VERSION 5.7 ;
  NOWIREEXTENSIONATPIN ON ;
  DIVIDERCHAR "/" ;
  BUSBITCHARS "[]" ;
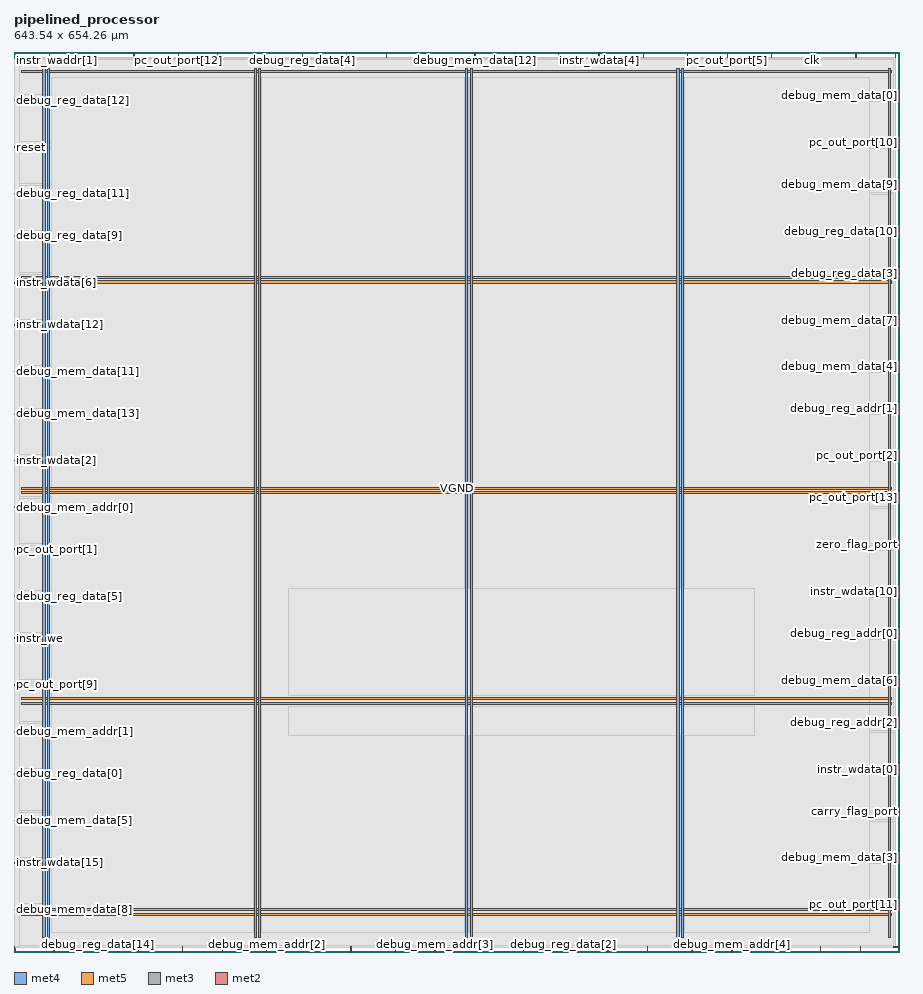
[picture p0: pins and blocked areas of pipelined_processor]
MACRO pipelined_processor
  CLASS BLOCK ;
  FOREIGN pipelined_processor ;
  ORIGIN 0.000 0.000 ;
  SIZE 643.540 BY 654.260 ;
  PIN VGND
    DIRECTION INOUT ;
    USE GROUND ;
    PORT
      LAYER met4 ;
        RECT 24.340 10.640 25.940 642.160 ;
    END
    PORT
      LAYER met4 ;
        RECT 177.940 10.640 179.540 642.160 ;
    END
    PORT
      LAYER met4 ;
        RECT 331.540 10.640 333.140 642.160 ;
    END
    PORT
      LAYER met4 ;
        RECT 485.140 10.640 486.740 642.160 ;
    END
    PORT
      LAYER met5 ;
        RECT 5.280 30.030 638.260 31.630 ;
    END
    PORT
      LAYER met5 ;
        RECT 5.280 183.210 638.260 184.810 ;
    END
    PORT
      LAYER met5 ;
        RECT 5.280 336.390 638.260 337.990 ;
    END
    PORT
      LAYER met5 ;
        RECT 5.280 489.570 638.260 491.170 ;
    END
  END VGND
  PIN VPWR
    DIRECTION INOUT ;
    USE POWER ;
    PORT
      LAYER met4 ;
        RECT 21.040 10.640 22.640 642.160 ;
    END
    PORT
      LAYER met4 ;
        RECT 174.640 10.640 176.240 642.160 ;
    END
    PORT
      LAYER met4 ;
        RECT 328.240 10.640 329.840 642.160 ;
    END
    PORT
      LAYER met4 ;
        RECT 481.840 10.640 483.440 642.160 ;
    END
    PORT
      LAYER met4 ;
        RECT 635.440 10.640 637.040 642.160 ;
    END
    PORT
      LAYER met5 ;
        RECT 5.280 26.730 638.260 28.330 ;
    END
    PORT
      LAYER met5 ;
        RECT 5.280 179.910 638.260 181.510 ;
    END
    PORT
      LAYER met5 ;
        RECT 5.280 333.090 638.260 334.690 ;
    END
    PORT
      LAYER met5 ;
        RECT 5.280 486.270 638.260 487.870 ;
    END
    PORT
      LAYER met5 ;
        RECT 5.280 639.450 638.260 641.050 ;
    END
  END VPWR
  PIN carry_flag_port
    DIRECTION OUTPUT TRISTATE ;
    USE SIGNAL ;
    ANTENNADIFFAREA 0.795200 ;
    PORT
      LAYER met3 ;
        RECT 639.540 102.040 643.540 102.640 ;
    END
  END carry_flag_port
  PIN clk
    DIRECTION INPUT ;
    USE SIGNAL ;
    ANTENNAGATEAREA 1.286700 ;
    ANTENNADIFFAREA 0.434700 ;
    PORT
      LAYER met2 ;
        RECT 579.690 650.260 579.970 654.260 ;
    END
  END clk
  PIN debug_mem_addr[0]
    DIRECTION INPUT ;
    USE SIGNAL ;
    ANTENNAGATEAREA 0.247500 ;
    PORT
      LAYER met3 ;
        RECT 0.000 323.040 4.000 323.640 ;
    END
  END debug_mem_addr[0]
  PIN debug_mem_addr[1]
    DIRECTION INPUT ;
    USE SIGNAL ;
    ANTENNAGATEAREA 0.213000 ;
    PORT
      LAYER met3 ;
        RECT 0.000 159.840 4.000 160.440 ;
    END
  END debug_mem_addr[1]
  PIN debug_mem_addr[2]
    DIRECTION INPUT ;
    USE SIGNAL ;
    ANTENNAGATEAREA 0.213000 ;
    PORT
      LAYER met2 ;
        RECT 183.630 0.000 183.910 4.000 ;
    END
  END debug_mem_addr[2]
  PIN debug_mem_addr[3]
    DIRECTION INPUT ;
    USE SIGNAL ;
    ANTENNAGATEAREA 0.159000 ;
    PORT
      LAYER met2 ;
        RECT 305.990 0.000 306.270 4.000 ;
    END
  END debug_mem_addr[3]
  PIN debug_mem_addr[4]
    DIRECTION INPUT ;
    USE SIGNAL ;
    ANTENNAGATEAREA 0.126000 ;
    PORT
      LAYER met2 ;
        RECT 521.730 0.000 522.010 4.000 ;
    END
  END debug_mem_addr[4]
  PIN debug_mem_addr[5]
    DIRECTION INPUT ;
    USE SIGNAL ;
    ANTENNAGATEAREA 0.126000 ;
    PORT
      LAYER met2 ;
        RECT 553.930 0.000 554.210 4.000 ;
    END
  END debug_mem_addr[5]
  PIN debug_mem_data[0]
    DIRECTION OUTPUT TRISTATE ;
    USE SIGNAL ;
    ANTENNADIFFAREA 0.445500 ;
    PORT
      LAYER met3 ;
        RECT 639.540 622.240 643.540 622.840 ;
    END
  END debug_mem_data[0]
  PIN debug_mem_data[10]
    DIRECTION OUTPUT TRISTATE ;
    USE SIGNAL ;
    ANTENNADIFFAREA 0.795200 ;
    PORT
      LAYER met2 ;
        RECT 87.030 650.260 87.310 654.260 ;
    END
  END debug_mem_data[10]
  PIN debug_mem_data[11]
    DIRECTION OUTPUT TRISTATE ;
    USE SIGNAL ;
    ANTENNADIFFAREA 0.795200 ;
    PORT
      LAYER met3 ;
        RECT 0.000 421.640 4.000 422.240 ;
    END
  END debug_mem_data[11]
  PIN debug_mem_data[12]
    DIRECTION OUTPUT TRISTATE ;
    USE SIGNAL ;
    ANTENNADIFFAREA 0.795200 ;
    PORT
      LAYER met2 ;
        RECT 334.970 650.260 335.250 654.260 ;
    END
  END debug_mem_data[12]
  PIN debug_mem_data[13]
    DIRECTION OUTPUT TRISTATE ;
    USE SIGNAL ;
    ANTENNADIFFAREA 0.795200 ;
    PORT
      LAYER met3 ;
        RECT 0.000 391.040 4.000 391.640 ;
    END
  END debug_mem_data[13]
  PIN debug_mem_data[14]
    DIRECTION OUTPUT TRISTATE ;
    USE SIGNAL ;
    ANTENNADIFFAREA 0.795200 ;
    PORT
      LAYER met3 ;
        RECT 639.540 3.440 643.540 4.040 ;
    END
  END debug_mem_data[14]
  PIN debug_mem_data[15]
    DIRECTION OUTPUT TRISTATE ;
    USE SIGNAL ;
    ANTENNADIFFAREA 0.795200 ;
    PORT
      LAYER met2 ;
        RECT 615.110 0.000 615.390 4.000 ;
    END
  END debug_mem_data[15]
  PIN debug_mem_data[1]
    DIRECTION OUTPUT TRISTATE ;
    USE SIGNAL ;
    ANTENNADIFFAREA 0.795200 ;
    PORT
      LAYER met2 ;
        RECT 363.950 650.260 364.230 654.260 ;
    END
  END debug_mem_data[1]
  PIN debug_mem_data[2]
    DIRECTION OUTPUT TRISTATE ;
    USE SIGNAL ;
    ANTENNADIFFAREA 0.795200 ;
    PORT
      LAYER met2 ;
        RECT 489.530 650.260 489.810 654.260 ;
    END
  END debug_mem_data[2]
  PIN debug_mem_data[3]
    DIRECTION OUTPUT TRISTATE ;
    USE SIGNAL ;
    ANTENNADIFFAREA 0.795200 ;
    PORT
      LAYER met3 ;
        RECT 639.540 68.040 643.540 68.640 ;
    END
  END debug_mem_data[3]
  PIN debug_mem_data[4]
    DIRECTION OUTPUT TRISTATE ;
    USE SIGNAL ;
    ANTENNADIFFAREA 0.445500 ;
    PORT
      LAYER met3 ;
        RECT 639.540 425.040 643.540 425.640 ;
    END
  END debug_mem_data[4]
  PIN debug_mem_data[5]
    DIRECTION OUTPUT TRISTATE ;
    USE SIGNAL ;
    ANTENNADIFFAREA 0.795200 ;
    PORT
      LAYER met3 ;
        RECT 0.000 95.240 4.000 95.840 ;
    END
  END debug_mem_data[5]
  PIN debug_mem_data[6]
    DIRECTION OUTPUT TRISTATE ;
    USE SIGNAL ;
    ANTENNADIFFAREA 0.445500 ;
    PORT
      LAYER met3 ;
        RECT 639.540 197.240 643.540 197.840 ;
    END
  END debug_mem_data[6]
  PIN debug_mem_data[7]
    DIRECTION OUTPUT TRISTATE ;
    USE SIGNAL ;
    ANTENNADIFFAREA 0.445500 ;
    PORT
      LAYER met3 ;
        RECT 639.540 459.040 643.540 459.640 ;
    END
  END debug_mem_data[7]
  PIN debug_mem_data[8]
    DIRECTION OUTPUT TRISTATE ;
    USE SIGNAL ;
    ANTENNADIFFAREA 0.795200 ;
    PORT
      LAYER met3 ;
        RECT 0.000 30.640 4.000 31.240 ;
    END
  END debug_mem_data[8]
  PIN debug_mem_data[9]
    DIRECTION OUTPUT TRISTATE ;
    USE SIGNAL ;
    ANTENNADIFFAREA 0.795200 ;
    PORT
      LAYER met3 ;
        RECT 639.540 557.640 643.540 558.240 ;
    END
  END debug_mem_data[9]
  PIN debug_reg_addr[0]
    DIRECTION INPUT ;
    USE SIGNAL ;
    ANTENNAGATEAREA 0.247500 ;
    PORT
      LAYER met3 ;
        RECT 639.540 231.240 643.540 231.840 ;
    END
  END debug_reg_addr[0]
  PIN debug_reg_addr[1]
    DIRECTION INPUT ;
    USE SIGNAL ;
    ANTENNAGATEAREA 0.213000 ;
    PORT
      LAYER met3 ;
        RECT 639.540 394.440 643.540 395.040 ;
    END
  END debug_reg_addr[1]
  PIN debug_reg_addr[2]
    DIRECTION INPUT ;
    USE SIGNAL ;
    ANTENNAGATEAREA 0.426000 ;
    PORT
      LAYER met3 ;
        RECT 639.540 166.640 643.540 167.240 ;
    END
  END debug_reg_addr[2]
  PIN debug_reg_data[0]
    DIRECTION OUTPUT TRISTATE ;
    USE SIGNAL ;
    ANTENNADIFFAREA 0.795200 ;
    PORT
      LAYER met3 ;
        RECT 0.000 129.240 4.000 129.840 ;
    END
  END debug_reg_data[0]
  PIN debug_reg_data[10]
    DIRECTION OUTPUT TRISTATE ;
    USE SIGNAL ;
    ANTENNADIFFAREA 0.795200 ;
    PORT
      LAYER met3 ;
        RECT 639.540 523.640 643.540 524.240 ;
    END
  END debug_reg_data[10]
  PIN debug_reg_data[11]
    DIRECTION OUTPUT TRISTATE ;
    USE SIGNAL ;
    ANTENNADIFFAREA 0.795200 ;
    PORT
      LAYER met3 ;
        RECT 0.000 550.840 4.000 551.440 ;
    END
  END debug_reg_data[11]
  PIN debug_reg_data[12]
    DIRECTION OUTPUT TRISTATE ;
    USE SIGNAL ;
    ANTENNADIFFAREA 0.795200 ;
    PORT
      LAYER met3 ;
        RECT 0.000 618.840 4.000 619.440 ;
    END
  END debug_reg_data[12]
  PIN debug_reg_data[13]
    DIRECTION OUTPUT TRISTATE ;
    USE SIGNAL ;
    ANTENNADIFFAREA 0.795200 ;
    PORT
      LAYER met3 ;
        RECT 0.000 649.440 4.000 650.040 ;
    END
  END debug_reg_data[13]
  PIN debug_reg_data[14]
    DIRECTION OUTPUT TRISTATE ;
    USE SIGNAL ;
    ANTENNADIFFAREA 0.795200 ;
    PORT
      LAYER met2 ;
        RECT 61.270 0.000 61.550 4.000 ;
    END
  END debug_reg_data[14]
  PIN debug_reg_data[15]
    DIRECTION OUTPUT TRISTATE ;
    USE SIGNAL ;
    ANTENNADIFFAREA 0.795200 ;
    PORT
      LAYER met2 ;
        RECT 396.150 650.260 396.430 654.260 ;
    END
  END debug_reg_data[15]
  PIN debug_reg_data[1]
    DIRECTION OUTPUT TRISTATE ;
    USE SIGNAL ;
    ANTENNADIFFAREA 0.795200 ;
    PORT
      LAYER met2 ;
        RECT 244.810 0.000 245.090 4.000 ;
    END
  END debug_reg_data[1]
  PIN debug_reg_data[2]
    DIRECTION OUTPUT TRISTATE ;
    USE SIGNAL ;
    ANTENNADIFFAREA 0.795200 ;
    PORT
      LAYER met2 ;
        RECT 399.370 0.000 399.650 4.000 ;
    END
  END debug_reg_data[2]
  PIN debug_reg_data[3]
    DIRECTION OUTPUT TRISTATE ;
    USE SIGNAL ;
    ANTENNADIFFAREA 0.445500 ;
    PORT
      LAYER met3 ;
        RECT 639.540 493.040 643.540 493.640 ;
    END
  END debug_reg_data[3]
  PIN debug_reg_data[4]
    DIRECTION OUTPUT TRISTATE ;
    USE SIGNAL ;
    ANTENNADIFFAREA 0.795200 ;
    PORT
      LAYER met2 ;
        RECT 209.390 650.260 209.670 654.260 ;
    END
  END debug_reg_data[4]
  PIN debug_reg_data[5]
    DIRECTION OUTPUT TRISTATE ;
    USE SIGNAL ;
    ANTENNADIFFAREA 0.795200 ;
    PORT
      LAYER met3 ;
        RECT 0.000 258.440 4.000 259.040 ;
    END
  END debug_reg_data[5]
  PIN debug_reg_data[6]
    DIRECTION OUTPUT TRISTATE ;
    USE SIGNAL ;
    ANTENNADIFFAREA 0.795200 ;
    PORT
      LAYER met2 ;
        RECT 151.430 0.000 151.710 4.000 ;
    END
  END debug_reg_data[6]
  PIN debug_reg_data[7]
    DIRECTION OUTPUT TRISTATE ;
    USE SIGNAL ;
    ANTENNADIFFAREA 0.795200 ;
    PORT
      LAYER met2 ;
        RECT 492.750 0.000 493.030 4.000 ;
    END
  END debug_reg_data[7]
  PIN debug_reg_data[8]
    DIRECTION OUTPUT TRISTATE ;
    USE SIGNAL ;
    ANTENNADIFFAREA 0.795200 ;
    PORT
      LAYER met2 ;
        RECT 457.330 650.260 457.610 654.260 ;
    END
  END debug_reg_data[8]
  PIN debug_reg_data[9]
    DIRECTION OUTPUT TRISTATE ;
    USE SIGNAL ;
    ANTENNADIFFAREA 0.795200 ;
    PORT
      LAYER met3 ;
        RECT 0.000 520.240 4.000 520.840 ;
    END
  END debug_reg_data[9]
  PIN instr_waddr[0]
    DIRECTION INPUT ;
    USE SIGNAL ;
    ANTENNAGATEAREA 0.426000 ;
    PORT
      LAYER met2 ;
        RECT 370.390 0.000 370.670 4.000 ;
    END
  END instr_waddr[0]
  PIN instr_waddr[1]
    DIRECTION INPUT ;
    USE SIGNAL ;
    ANTENNAGATEAREA 0.159000 ;
    PORT
      LAYER met2 ;
        RECT 25.850 650.260 26.130 654.260 ;
    END
  END instr_waddr[1]
  PIN instr_waddr[2]
    DIRECTION INPUT ;
    USE SIGNAL ;
    ANTENNAGATEAREA 0.495000 ;
    PORT
      LAYER met2 ;
        RECT 586.130 0.000 586.410 4.000 ;
    END
  END instr_waddr[2]
  PIN instr_waddr[3]
    DIRECTION INPUT ;
    USE SIGNAL ;
    ANTENNAGATEAREA 0.213000 ;
    PORT
      LAYER met2 ;
        RECT 241.590 650.260 241.870 654.260 ;
    END
  END instr_waddr[3]
  PIN instr_wdata[0]
    DIRECTION INPUT ;
    USE SIGNAL ;
    ANTENNAGATEAREA 0.495000 ;
    PORT
      LAYER met3 ;
        RECT 639.540 132.640 643.540 133.240 ;
    END
  END instr_wdata[0]
  PIN instr_wdata[10]
    DIRECTION INPUT ;
    USE SIGNAL ;
    ANTENNAGATEAREA 0.247500 ;
    PORT
      LAYER met3 ;
        RECT 639.540 261.840 643.540 262.440 ;
    END
  END instr_wdata[10]
  PIN instr_wdata[11]
    DIRECTION INPUT ;
    USE SIGNAL ;
    ANTENNAGATEAREA 0.426000 ;
    PORT
      LAYER met2 ;
        RECT 460.550 0.000 460.830 4.000 ;
    END
  END instr_wdata[11]
  PIN instr_wdata[12]
    DIRECTION INPUT ;
    USE SIGNAL ;
    ANTENNAGATEAREA 0.196500 ;
    PORT
      LAYER met3 ;
        RECT 0.000 455.640 4.000 456.240 ;
    END
  END instr_wdata[12]
  PIN instr_wdata[13]
    DIRECTION INPUT ;
    USE SIGNAL ;
    ANTENNAGATEAREA 0.159000 ;
    PORT
      LAYER met2 ;
        RECT 180.410 650.260 180.690 654.260 ;
    END
  END instr_wdata[13]
  PIN instr_wdata[14]
    DIRECTION INPUT ;
    USE SIGNAL ;
    ANTENNAGATEAREA 0.213000 ;
    PORT
      LAYER met2 ;
        RECT 302.770 650.260 303.050 654.260 ;
    END
  END instr_wdata[14]
  PIN instr_wdata[15]
    DIRECTION INPUT ;
    USE SIGNAL ;
    ANTENNAGATEAREA 0.213000 ;
    PORT
      LAYER met3 ;
        RECT 0.000 64.640 4.000 65.240 ;
    END
  END instr_wdata[15]
  PIN instr_wdata[1]
    DIRECTION INPUT ;
    USE SIGNAL ;
    ANTENNAGATEAREA 0.213000 ;
    PORT
      LAYER met2 ;
        RECT 0.090 0.000 0.370 4.000 ;
    END
  END instr_wdata[1]
  PIN instr_wdata[2]
    DIRECTION INPUT ;
    USE SIGNAL ;
    ANTENNAGATEAREA 0.126000 ;
    PORT
      LAYER met3 ;
        RECT 0.000 357.040 4.000 357.640 ;
    END
  END instr_wdata[2]
  PIN instr_wdata[3]
    DIRECTION INPUT ;
    USE SIGNAL ;
    ANTENNAGATEAREA 0.213000 ;
    PORT
      LAYER met2 ;
        RECT 270.570 650.260 270.850 654.260 ;
    END
  END instr_wdata[3]
  PIN instr_wdata[4]
    DIRECTION INPUT ;
    USE SIGNAL ;
    ANTENNAGATEAREA 0.213000 ;
    PORT
      LAYER met2 ;
        RECT 425.130 650.260 425.410 654.260 ;
    END
  END instr_wdata[4]
  PIN instr_wdata[5]
    DIRECTION INPUT ;
    USE SIGNAL ;
    ANTENNAGATEAREA 0.247500 ;
    PORT
      LAYER met2 ;
        RECT 611.890 650.260 612.170 654.260 ;
    END
  END instr_wdata[5]
  PIN instr_wdata[6]
    DIRECTION INPUT ;
    USE SIGNAL ;
    ANTENNAGATEAREA 0.213000 ;
    PORT
      LAYER met3 ;
        RECT 0.000 486.240 4.000 486.840 ;
    END
  END instr_wdata[6]
  PIN instr_wdata[7]
    DIRECTION INPUT ;
    USE SIGNAL ;
    ANTENNAGATEAREA 0.247500 ;
    PORT
      LAYER met2 ;
        RECT 90.250 0.000 90.530 4.000 ;
    END
  END instr_wdata[7]
  PIN instr_wdata[8]
    DIRECTION INPUT ;
    USE SIGNAL ;
    ANTENNAGATEAREA 0.213000 ;
    PORT
      LAYER met2 ;
        RECT 29.070 0.000 29.350 4.000 ;
    END
  END instr_wdata[8]
  PIN instr_wdata[9]
    DIRECTION INPUT ;
    USE SIGNAL ;
    ANTENNAGATEAREA 0.426000 ;
    PORT
      LAYER met2 ;
        RECT 640.870 650.260 641.150 654.260 ;
    END
  END instr_wdata[9]
  PIN instr_we
    DIRECTION INPUT ;
    USE SIGNAL ;
    ANTENNAGATEAREA 0.159000 ;
    PORT
      LAYER met3 ;
        RECT 0.000 227.840 4.000 228.440 ;
    END
  END instr_we
  PIN pc_out_port[0]
    DIRECTION OUTPUT TRISTATE ;
    USE SIGNAL ;
    ANTENNADIFFAREA 0.795200 ;
    PORT
      LAYER met2 ;
        RECT 277.010 0.000 277.290 4.000 ;
    END
  END pc_out_port[0]
  PIN pc_out_port[10]
    DIRECTION OUTPUT TRISTATE ;
    USE SIGNAL ;
    ANTENNADIFFAREA 0.445500 ;
    PORT
      LAYER met3 ;
        RECT 639.540 588.240 643.540 588.840 ;
    END
  END pc_out_port[10]
  PIN pc_out_port[11]
    DIRECTION OUTPUT TRISTATE ;
    USE SIGNAL ;
    ANTENNADIFFAREA 0.795200 ;
    PORT
      LAYER met3 ;
        RECT 639.540 34.040 643.540 34.640 ;
    END
  END pc_out_port[11]
  PIN pc_out_port[12]
    DIRECTION OUTPUT TRISTATE ;
    USE SIGNAL ;
    ANTENNADIFFAREA 0.795200 ;
    PORT
      LAYER met2 ;
        RECT 119.230 650.260 119.510 654.260 ;
    END
  END pc_out_port[12]
  PIN pc_out_port[13]
    DIRECTION OUTPUT TRISTATE ;
    USE SIGNAL ;
    ANTENNADIFFAREA 0.445500 ;
    PORT
      LAYER met3 ;
        RECT 639.540 329.840 643.540 330.440 ;
    END
  END pc_out_port[13]
  PIN pc_out_port[14]
    DIRECTION OUTPUT TRISTATE ;
    USE SIGNAL ;
    ANTENNADIFFAREA 0.795200 ;
    PORT
      LAYER met2 ;
        RECT 122.450 0.000 122.730 4.000 ;
    END
  END pc_out_port[14]
  PIN pc_out_port[15]
    DIRECTION OUTPUT TRISTATE ;
    USE SIGNAL ;
    ANTENNADIFFAREA 0.795200 ;
    PORT
      LAYER met2 ;
        RECT 215.830 0.000 216.110 4.000 ;
    END
  END pc_out_port[15]
  PIN pc_out_port[1]
    DIRECTION OUTPUT TRISTATE ;
    USE SIGNAL ;
    ANTENNADIFFAREA 0.795200 ;
    PORT
      LAYER met3 ;
        RECT 0.000 292.440 4.000 293.040 ;
    END
  END pc_out_port[1]
  PIN pc_out_port[2]
    DIRECTION OUTPUT TRISTATE ;
    USE SIGNAL ;
    ANTENNADIFFAREA 0.445500 ;
    PORT
      LAYER met3 ;
        RECT 639.540 360.440 643.540 361.040 ;
    END
  END pc_out_port[2]
  PIN pc_out_port[3]
    DIRECTION OUTPUT TRISTATE ;
    USE SIGNAL ;
    ANTENNADIFFAREA 0.795200 ;
    PORT
      LAYER met2 ;
        RECT 338.190 0.000 338.470 4.000 ;
    END
  END pc_out_port[3]
  PIN pc_out_port[4]
    DIRECTION OUTPUT TRISTATE ;
    USE SIGNAL ;
    ANTENNADIFFAREA 0.795200 ;
    PORT
      LAYER met2 ;
        RECT 550.710 650.260 550.990 654.260 ;
    END
  END pc_out_port[4]
  PIN pc_out_port[5]
    DIRECTION OUTPUT TRISTATE ;
    USE SIGNAL ;
    ANTENNADIFFAREA 0.795200 ;
    PORT
      LAYER met2 ;
        RECT 518.510 650.260 518.790 654.260 ;
    END
  END pc_out_port[5]
  PIN pc_out_port[6]
    DIRECTION OUTPUT TRISTATE ;
    USE SIGNAL ;
    ANTENNADIFFAREA 0.795200 ;
    PORT
      LAYER met2 ;
        RECT 54.830 650.260 55.110 654.260 ;
    END
  END pc_out_port[6]
  PIN pc_out_port[7]
    DIRECTION OUTPUT TRISTATE ;
    USE SIGNAL ;
    ANTENNADIFFAREA 0.795200 ;
    PORT
      LAYER met2 ;
        RECT 148.210 650.260 148.490 654.260 ;
    END
  END pc_out_port[7]
  PIN pc_out_port[8]
    DIRECTION OUTPUT TRISTATE ;
    USE SIGNAL ;
    ANTENNADIFFAREA 0.795200 ;
    PORT
      LAYER met2 ;
        RECT 431.570 0.000 431.850 4.000 ;
    END
  END pc_out_port[8]
  PIN pc_out_port[9]
    DIRECTION OUTPUT TRISTATE ;
    USE SIGNAL ;
    ANTENNADIFFAREA 0.795200 ;
    PORT
      LAYER met3 ;
        RECT 0.000 193.840 4.000 194.440 ;
    END
  END pc_out_port[9]
  PIN reset
    DIRECTION INPUT ;
    USE SIGNAL ;
    ANTENNAGATEAREA 0.247500 ;
    PORT
      LAYER met3 ;
        RECT 0.000 584.840 4.000 585.440 ;
    END
  END reset
  PIN zero_flag_port
    DIRECTION OUTPUT TRISTATE ;
    USE SIGNAL ;
    ANTENNADIFFAREA 0.795200 ;
    PORT
      LAYER met3 ;
        RECT 639.540 295.840 643.540 296.440 ;
    END
  END zero_flag_port
  OBS
      LAYER li1 ;
        RECT 5.520 10.795 638.020 642.005 ;
      LAYER met1 ;
        RECT 0.070 10.640 641.170 642.160 ;
      LAYER met2 ;
        RECT 0.100 649.980 25.570 650.260 ;
        RECT 26.410 649.980 54.550 650.260 ;
        RECT 55.390 649.980 86.750 650.260 ;
        RECT 87.590 649.980 118.950 650.260 ;
        RECT 119.790 649.980 147.930 650.260 ;
        RECT 148.770 649.980 180.130 650.260 ;
        RECT 180.970 649.980 209.110 650.260 ;
        RECT 209.950 649.980 241.310 650.260 ;
        RECT 242.150 649.980 270.290 650.260 ;
        RECT 271.130 649.980 302.490 650.260 ;
        RECT 303.330 649.980 334.690 650.260 ;
        RECT 335.530 649.980 363.670 650.260 ;
        RECT 364.510 649.980 395.870 650.260 ;
        RECT 396.710 649.980 424.850 650.260 ;
        RECT 425.690 649.980 457.050 650.260 ;
        RECT 457.890 649.980 489.250 650.260 ;
        RECT 490.090 649.980 518.230 650.260 ;
        RECT 519.070 649.980 550.430 650.260 ;
        RECT 551.270 649.980 579.410 650.260 ;
        RECT 580.250 649.980 611.610 650.260 ;
        RECT 612.450 649.980 640.590 650.260 ;
        RECT 0.100 4.280 641.140 649.980 ;
        RECT 0.650 3.555 28.790 4.280 ;
        RECT 29.630 3.555 60.990 4.280 ;
        RECT 61.830 3.555 89.970 4.280 ;
        RECT 90.810 3.555 122.170 4.280 ;
        RECT 123.010 3.555 151.150 4.280 ;
        RECT 151.990 3.555 183.350 4.280 ;
        RECT 184.190 3.555 215.550 4.280 ;
        RECT 216.390 3.555 244.530 4.280 ;
        RECT 245.370 3.555 276.730 4.280 ;
        RECT 277.570 3.555 305.710 4.280 ;
        RECT 306.550 3.555 337.910 4.280 ;
        RECT 338.750 3.555 370.110 4.280 ;
        RECT 370.950 3.555 399.090 4.280 ;
        RECT 399.930 3.555 431.290 4.280 ;
        RECT 432.130 3.555 460.270 4.280 ;
        RECT 461.110 3.555 492.470 4.280 ;
        RECT 493.310 3.555 521.450 4.280 ;
        RECT 522.290 3.555 553.650 4.280 ;
        RECT 554.490 3.555 585.850 4.280 ;
        RECT 586.690 3.555 614.830 4.280 ;
        RECT 615.670 3.555 641.140 4.280 ;
      LAYER met3 ;
        RECT 4.400 649.040 639.540 649.890 ;
        RECT 3.990 623.240 639.540 649.040 ;
        RECT 3.990 621.840 639.140 623.240 ;
        RECT 3.990 619.840 639.540 621.840 ;
        RECT 4.400 618.440 639.540 619.840 ;
        RECT 3.990 589.240 639.540 618.440 ;
        RECT 3.990 587.840 639.140 589.240 ;
        RECT 3.990 585.840 639.540 587.840 ;
        RECT 4.400 584.440 639.540 585.840 ;
        RECT 3.990 558.640 639.540 584.440 ;
        RECT 3.990 557.240 639.140 558.640 ;
        RECT 3.990 551.840 639.540 557.240 ;
        RECT 4.400 550.440 639.540 551.840 ;
        RECT 3.990 524.640 639.540 550.440 ;
        RECT 3.990 523.240 639.140 524.640 ;
        RECT 3.990 521.240 639.540 523.240 ;
        RECT 4.400 519.840 639.540 521.240 ;
        RECT 3.990 494.040 639.540 519.840 ;
        RECT 3.990 492.640 639.140 494.040 ;
        RECT 3.990 487.240 639.540 492.640 ;
        RECT 4.400 485.840 639.540 487.240 ;
        RECT 3.990 460.040 639.540 485.840 ;
        RECT 3.990 458.640 639.140 460.040 ;
        RECT 3.990 456.640 639.540 458.640 ;
        RECT 4.400 455.240 639.540 456.640 ;
        RECT 3.990 426.040 639.540 455.240 ;
        RECT 3.990 424.640 639.140 426.040 ;
        RECT 3.990 422.640 639.540 424.640 ;
        RECT 4.400 421.240 639.540 422.640 ;
        RECT 3.990 395.440 639.540 421.240 ;
        RECT 3.990 394.040 639.140 395.440 ;
        RECT 3.990 392.040 639.540 394.040 ;
        RECT 4.400 390.640 639.540 392.040 ;
        RECT 3.990 361.440 639.540 390.640 ;
        RECT 3.990 360.040 639.140 361.440 ;
        RECT 3.990 358.040 639.540 360.040 ;
        RECT 4.400 356.640 639.540 358.040 ;
        RECT 3.990 330.840 639.540 356.640 ;
        RECT 3.990 329.440 639.140 330.840 ;
        RECT 3.990 324.040 639.540 329.440 ;
        RECT 4.400 322.640 639.540 324.040 ;
        RECT 3.990 296.840 639.540 322.640 ;
        RECT 3.990 295.440 639.140 296.840 ;
        RECT 3.990 293.440 639.540 295.440 ;
        RECT 4.400 292.040 639.540 293.440 ;
        RECT 3.990 262.840 639.540 292.040 ;
        RECT 3.990 261.440 639.140 262.840 ;
        RECT 3.990 259.440 639.540 261.440 ;
        RECT 4.400 258.040 639.540 259.440 ;
        RECT 3.990 232.240 639.540 258.040 ;
        RECT 3.990 230.840 639.140 232.240 ;
        RECT 3.990 228.840 639.540 230.840 ;
        RECT 4.400 227.440 639.540 228.840 ;
        RECT 3.990 198.240 639.540 227.440 ;
        RECT 3.990 196.840 639.140 198.240 ;
        RECT 3.990 194.840 639.540 196.840 ;
        RECT 4.400 193.440 639.540 194.840 ;
        RECT 3.990 167.640 639.540 193.440 ;
        RECT 3.990 166.240 639.140 167.640 ;
        RECT 3.990 160.840 639.540 166.240 ;
        RECT 4.400 159.440 639.540 160.840 ;
        RECT 3.990 133.640 639.540 159.440 ;
        RECT 3.990 132.240 639.140 133.640 ;
        RECT 3.990 130.240 639.540 132.240 ;
        RECT 4.400 128.840 639.540 130.240 ;
        RECT 3.990 103.040 639.540 128.840 ;
        RECT 3.990 101.640 639.140 103.040 ;
        RECT 3.990 96.240 639.540 101.640 ;
        RECT 4.400 94.840 639.540 96.240 ;
        RECT 3.990 69.040 639.540 94.840 ;
        RECT 3.990 67.640 639.140 69.040 ;
        RECT 3.990 65.640 639.540 67.640 ;
        RECT 4.400 64.240 639.540 65.640 ;
        RECT 3.990 35.040 639.540 64.240 ;
        RECT 3.990 33.640 639.140 35.040 ;
        RECT 3.990 31.640 639.540 33.640 ;
        RECT 4.400 30.240 639.540 31.640 ;
        RECT 3.990 4.440 639.540 30.240 ;
        RECT 3.990 3.575 639.140 4.440 ;
      LAYER met4 ;
        RECT 26.975 14.455 174.240 635.625 ;
        RECT 176.640 14.455 177.540 635.625 ;
        RECT 179.940 14.455 327.840 635.625 ;
        RECT 330.240 14.455 331.140 635.625 ;
        RECT 333.540 14.455 481.440 635.625 ;
        RECT 483.840 14.455 484.740 635.625 ;
        RECT 487.140 14.455 621.625 635.625 ;
      LAYER met5 ;
        RECT 199.300 186.410 538.540 264.300 ;
        RECT 199.300 157.300 538.540 178.310 ;
  END
END pipelined_processor
END LIBRARY

